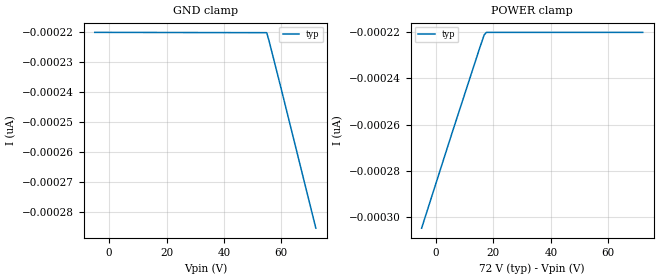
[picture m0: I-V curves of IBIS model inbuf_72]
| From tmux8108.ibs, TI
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| inbuf_72
[Model]   inbuf_72
Model_type   Input
Vinl = 1.3
Vinh = 0.8
|   typ   min   max
C_comp   1.598234e-13   NA   NA
[Voltage Range]   72   NA   NA
[Temperature Range]   27   NA   NA
[Power Clamp Reference]   72   NA   NA
[GND Clamp Reference]   0   NA   NA
[GND Clamp]
|   Voltage   I(typ)   I(min)   I(max)
-5V       -220pA     NA         NA
54.89V    -220.1pA   NA         NA
55.67V    -222.7pA   NA         NA
59.56V    -237.4pA   NA         NA
72V       -285.4pA   NA         NA
[POWER Clamp]
|   Voltage   I(typ)   I(min)   I(max)
-5V       -304.9pA   NA         NA
5.889V    -262.5pA   NA         NA
15.22V    -226.8pA   NA         NA
16.78V    -221.1pA   NA         NA
17.56V    -220pA     NA         NA
72V       -220pA     NA         NA
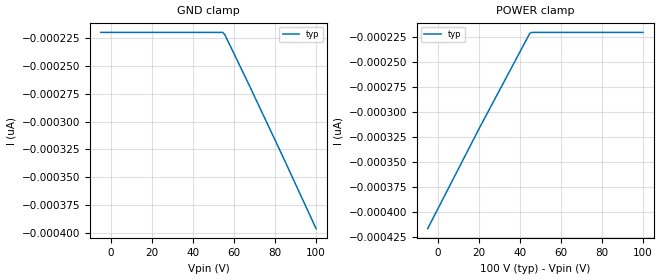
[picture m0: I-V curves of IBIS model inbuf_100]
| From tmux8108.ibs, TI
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| inbuf_100
[Model]   inbuf_100
Model_type   Input
Vinl = 1.3
Vinh = 0.8
|   typ   min   max
C_comp   1.598234e-13   NA   NA
[Voltage Range]   100   NA   NA
[Temperature Range]   27   NA   NA
[Power Clamp Reference]   100   NA   NA
[GND Clamp Reference]   0   NA   NA
[GND Clamp]
|   Voltage   I(typ)   I(min)   I(max)
-5V       -220pA     NA         NA
54.39V    -220pA     NA         NA
55.45V    -221.9pA   NA         NA
67.12V    -266.4pA   NA         NA
83.03V    -328.5pA   NA         NA
100V      -396.1pA   NA         NA
[POWER Clamp]
|   Voltage   I(typ)   I(min)   I(max)
-5V       -416.4pA   NA         NA
20.45V    -314.8pA   NA         NA
44.85V    -220.8pA   NA         NA
45.91V    -220pA     NA         NA
100V      -220pA     NA         NA
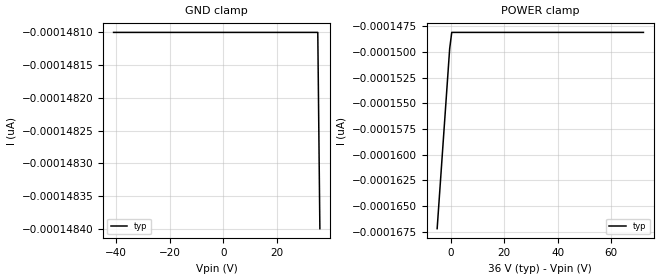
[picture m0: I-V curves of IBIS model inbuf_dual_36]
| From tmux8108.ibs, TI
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| inbuf_dual_36
[Model]   inbuf_dual_36
Model_type   Input
Vinl = 1.3
Vinh = 0.8
|   typ   min   max
C_comp   4.014581e-13   NA   NA
[Voltage Range]   36   NA   NA
[Temperature Range]   27   NA   NA
[Power Clamp Reference]   36   NA   NA
[GND Clamp Reference]   0   NA   NA
[GND Clamp]
|   Voltage   I(typ)   I(min)   I(max)
-41V      -148.1pA   NA         NA
-40.22V   -148.1pA   NA         NA
35.22V    -148.1pA   NA         NA
36V       -148.4pA   NA         NA
[POWER Clamp]
|   Voltage   I(typ)   I(min)   I(max)
-5V       -167.2pA   NA         NA
-333.3mV  -149.7pA   NA         NA
444.4mV   -148.1pA   NA         NA
72V       -148.1pA   NA         NA
